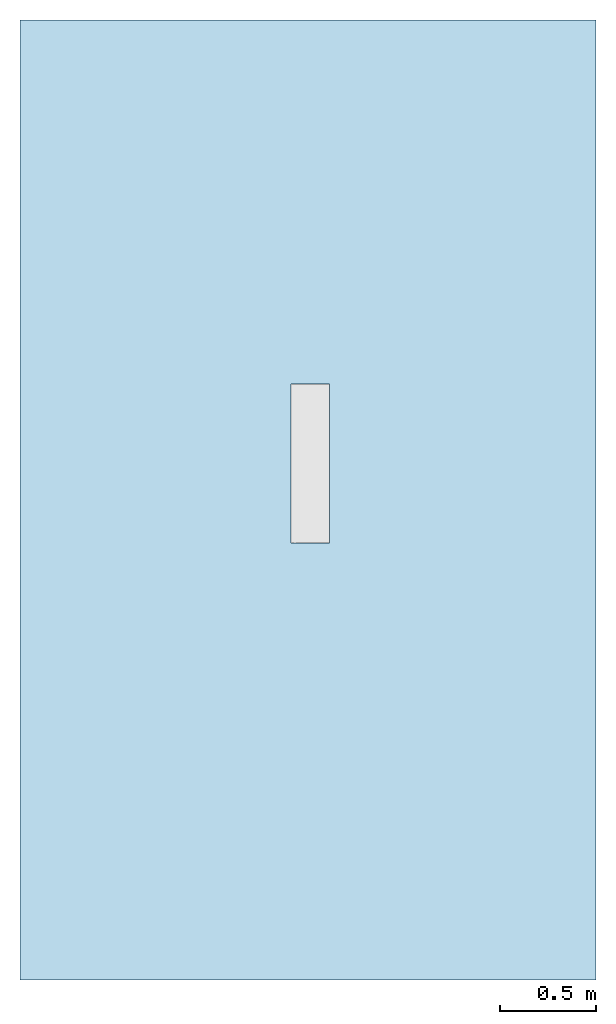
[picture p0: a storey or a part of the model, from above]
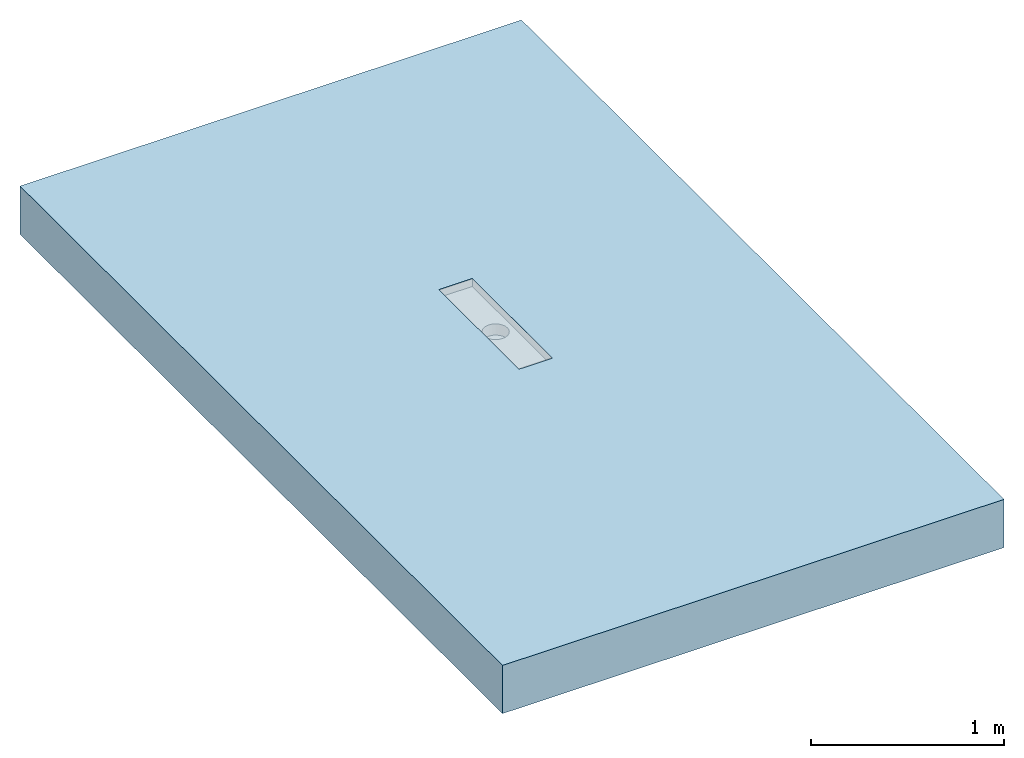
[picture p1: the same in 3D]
Properties of the parts of a building model (IFC2X3)

# File
Description: ViewDefinition [CoordinationView]
File name: Project Number
Time: 2016-11-22T10:18:11
Written by: The EXPRESS Data Manager Version 5.01.0100.02.64mod : 6 Jun 2012
Made in: 20130308_1515(x64) - Exporter 2014.0.2013.0308 - Default UI
Comment: STEP Physical File produced by: The EXPRESS Data Manager Version 5.01.0100.02.64mod : 6 Jun 2012 * Module: EDMstepFileFactory/EDMstandAlone * Creation date: Tue Nov 22 10:18:11 2016 * Host: IN-BLR-PC-0012 * Database: C:\Users\pakumar\AppData\Local\Temp\{BBC05A85-00B9-449C-89BD-49E8E6ED854E}\ifc * Database version: 5507 * Database creation date: Tue Nov 22 10:18:10 2016 * Schema: IFC2X3 * Model: DataRepository.ifc * Model creation date: Tue Nov 22 10:18:11 2016 * Header model: DataRepository.ifc_HeaderModel * Header model creation date: Tue Nov 22 10:18:11 2016 * EDMuser: sdai-user * EDMgroup: sdai-group * License ID and type: 5605 : Permanent license. Expiry date: * EDMstepFileFactory options: 020000

# IfcProject, Project Number
LongName: Project Name; Phase: Project Status

# IfcSite, Default
RefLatitude: 42, 21, 30, 344238; RefLongitude: -71, -3, -35, -194702; RefElevation: 0 mm

# IfcBuilding
Pset_BuildingCommon - NumberOfStoreys: 1
Other - Project Name: Project Name; Project Number: Project Number; Client Name: Owner; Project Issue Date: Issue Date; Project Address: Enter address here; Project Status: Project Status

# IfcBuildingStorey, Level 1
LongName: Level 1; Elevation: 0 mm
Graphics - Line Pattern: Grid Line 1/2"; Color: 0; Symbol at End 1 Default: no; Line Weight: 1; Symbol at End 2 Default: yes; Symbol: Level Head - Circle: Level Head - Circle
Constraints - Elevation Base: Project Base Point; Elevation: 0 mm
Identity Data - Name: Level 1; Structural: no; Building Story: yes
Dimensions - Computation Height: 0 mm

# IfcFlowTerminal: 416591 - Hygienic Standard Channel - with Gully 157 - 800mm LG - 200mm Wide, ACO Tray Channel - Hygienic - Standard - 200mm Wide:416591 - Hygienic Standard Channel - with Gully 157 - 800mm LG - 200mm Wide:470741
In: Level 1
Material: Stainless Steel AISI 304, Stainless Steel AISI 304 - Grating
General - Channel Dimension: 200 x 830; Load Class: A15 - C250 (EN 1253); Channel Colour: passivated stainless steel surface ( matt grey); Weight (Kg): 4.0; Product Code: 416591; Channel Material: Stainless steel 1.4301 (EN 10088); Outlet Diameter (mm): 142; Foul air trap seal Material: NBR; Product Type: Standard Kitchen Tray Channel; Maintenance guidelines: http://issuu.com/acobuildingdrainage/docs/aco_hygiene_first_catalogue/17?e=0; Channel Recycled material content: 20 - 30 %; Foul air trap Recyclable: Fully recyclable; Product Description: ACO Hygiene First Standard Kitchen Tray Channel 200 x 830 / 142 Dia Outlet & Foul Air Trap; Foul air trap seal Colour: Black; Product Standard: EN 1253 / EN 1672 / EN ISO 14159; Installation guidelines: http://issuu.com/acobuildingdrainage/docs/aco_hygiene_first_catalogue/17?e=0; Channel Recyclable: Fully recyclable; Price: POA - contact ACO; Foul air trap Recycled material content: 0%; Product Range: ACO Hygiene First
Phasing - Phase Created: New Construction
Mechanical - System Classification: Sanitary
Construction - 416808 - 168 x 398mm - Ladder Grating - R50 - Stainless steel 1.4301: no; 416948 - 168 x 399mm - Casted Grating - M125 - Stainless steel 1.4301: no; 416802 - 168 x 499mm - Ladder Grating - R50 - Stainless steel 1.4301: no; 416947 - 168 x 499mm - Casted Grating - M125 - Stainless steel 1.4301: yes; 416862 - 168 x 398mm - Mesh Grating - L15 - Stainless steel 1.4301: no; 416880 - 168 x 499mm - Mesh Grating - L15 - Stainless steel 1.4301: no; 416882 - 168 x 398mm - Mesh Grating - L15 - Stainless steel 1.4301: no; 416860 - 168 x 499mm - Mesh Grating - L15 - Stainless steel 1.4301: no; 416810 - 168 x 398mm - Ladder Grating - M125 - Stainless steel 1.4301: no; 416804 - 168 x 499mm - Ladder Grating - M125 - Stainless steel 1.4301: no; Detail - Outlet 110mm: no; Detail - Outlet 125mm: no; Detail - Outlet 142mm: yes; Grating: yes
Constraints - Level: Level: Level 1
Identity Data - Mark: 38; Telephone: +44 (0)1462 816666; Address: ACO Business Centre, Caxton Road, Bedford, MK41 0LF; Website: www.acobd.com; Cost: 0; Watermark2: This file is water marked and users are prohibited to reproduce, adapt, distribute this information; Watermarked With: BIM Manager Premium Suite; Manufacturer: ACO Building Drainage; Fax: +44 (0)1462 851490; E-mail Technical: abdtechnical@aco.co.uk; Watermark1: This file is the property of ACO Technologies PLC; E-mail Sales: abdcommercial@aco.co.uk; Watermarked By: www.acobd.com
Pset_ManufacturerTypeInformation - Manufacturer: ACO Building Drainage
Dimensions - End Plate: 800 mm; Outside Outlet Rad: 71 mm; Inside Outlet Rad: 69 mm; Endplate Position: 800 mm; Spigot Distance: 400 mm; Grating Height: 21 mm; Floor Cut Void Height: 62.8 mm; Grating Void Cut Length: 500 mm; End Connection Plate Start: -770 mm; Depth: 29 mm; Outlet: 142 mm; x: -815 mm; Number of gratings: 2; Invert Depth: 50 mm; Grating Length: 399 mm; End Connection Plate End: -800 mm; Length Channel: -770 mm
Other - Invert Depth Detail: 51.5 mm; Array: 32; Spigot Outlets Channels: yes; Flow: 0.0988811 m3/s; Length 1000: no; Length 1200: no; Length 2000: no; Length 500: no; Length 800: yes; Length 1500: no
Model Properties - Grating Product Code 416804: N/A; Grating Product Code 416862: Load Class L 15 (EN 1253) - Mesh Grate - Stainless steel 1.4301 (EN 10088) - 168 x 398 - 1.7kg; Grating Product Code 416810: Load Class M 125 (EN 1253) - Ladder Grate - Stainless steel 1.4301 (EN 10088) - 168 x 398 - 3.5kg; Grating Product Code 416860: N/A; Grating Product Code 416947: N/A; Grating Product Code 416808: Load Class R 50 (EN 1253) - Ladder Grate - Stainless steel 1.4301 (EN 10088) - 168 x 398 - 2.3kg; Grating Product Code 416948: Load Class M 125 (EN 1253) - Caste Grate - Stainless steel 1.4301 (EN 10088) - 168 x 399 - 5kg; Grating Product Code 416880: N/A; Grating Product Code 416882: Load Class L 15 (EN 1253) - Mesh Grate - Stainless steel 1.4301 (EN 10088) - 168 x 398 - 1.8kg; Grating Product Code 416802: N/A

# IfcOpeningElement: Recess
In: Level 1
Phasing - Phase Created: New Construction
Structural - Structural: no; Enable Analytical Model: no
Dimensions - Volume: 161.126 ft3; Thickness: 304.8 mm; Area: 161.459 ft2; Perimeter: 16000 mm
Constraints - Related to Mass: no; Room Bounding: yes; Level: Level: Level 1; Height Offset From Level: 0 mm
Identity Data - Assembly Description: Floor Construction; Assembly Code: B1010
Graphics - Coarse Scale Fill Color: 0
Analytical Properties - Roughness: 3; Absorptance: 0.7
Construction - Function: Interior; Default Thickness: 304.8 mm

# IfcSlab: Floor:Generic - 12", Floor:Generic - 12":184145
In: Level 1
PredefinedType: FLOOR; Material: Default Floor 304.8 mm
Phasing - Phase Created: New Construction
Structural - Structural: no; Enable Analytical Model: no
Dimensions - Volume: 161.126 ft3; Thickness: 304.8 mm; Area: 161.459 ft2; Perimeter: 16000 mm
Constraints - Related to Mass: no; Room Bounding: yes; Level: Level: Level 1; Height Offset From Level: 0 mm
Pset_SlabCommon - Reference: Generic - 12"; IsExternal: no; LoadBearing: yes
Identity Data - Assembly Description: Floor Construction; Assembly Code: B1010
Graphics - Coarse Scale Fill Color: 0
Analytical Properties - Roughness: 3; Absorptance: 0.7
Construction - Function: Interior; Default Thickness: 304.8 mm
